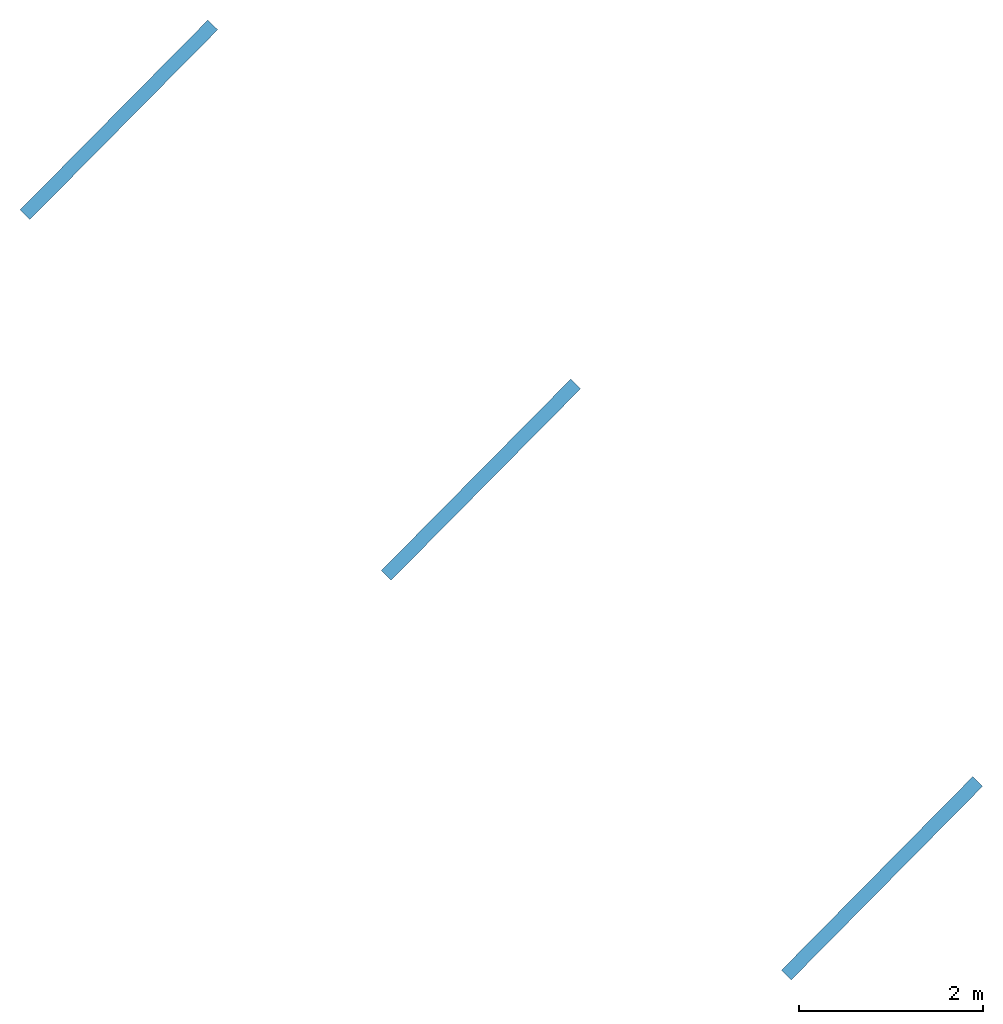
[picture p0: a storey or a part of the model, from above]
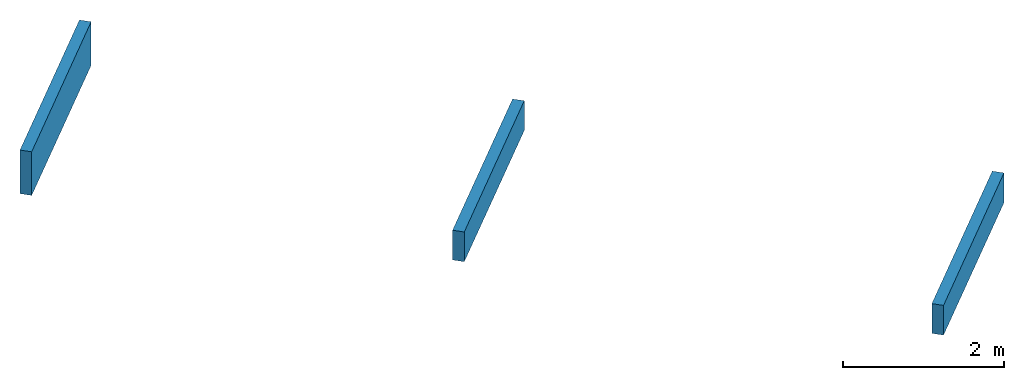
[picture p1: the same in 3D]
Properties of the parts of a building model (IFC2X3), part 1 of 2

# File
Description: ViewDefinition [CoordinationView]
File name: ZV001-350-201.1 (EDITED).ifc (Edited by Naviate Simple BIM 2022 version 6)
Time: 2026-03-20T15:17:01+01:00
Written by: ODA SDAI 24.12
Made in: Autodesk Revit 25.4.30.30 (ENU) - IFC 25.4.0.27

# IfcProject, 10001574
LongName: ENZV Kommersielt areal innland (KAI); Phase: Hovedprosjekt: 01.12.2018

# IfcSite, ENZV
RefLatitude: 59, 54, 57, 601318; RefLongitude: 10, 44, 59, 999999; RefElevation: 0 mm
Text - 02_IfcSite: STAVANGER LUFTHAVN; 01_Modellfil: zv001-a-200-1-0003.rvt; Prosjektleder: Livar Husveg; Tiltaket gjelder: Kommersielt areal innland, KAI
Identity Data - Building Name: ZV001; Inventarnr.: ZV001; CQIncludeDoorSwing: no; CQIncludeRoomNumber: no; CQIncludeRoomNumberWindows: no; CQIncludeWindowSwing: no; Workset: Project Info; Organization Description: BIM 360://Avinor - Stavanger lufthavn/ENZV_ARK_bygg A.rvt; Prosjekt: Stavanger lufthavn, Sola
Other - Project Number: 10001574; CQDoorSwingCodes: Left=V;Right=H;notMirrored =L;mirrored =R; Project Issue Date: Tilbudsprosjekt: 22.07.2018; CQWindowSwingCodes: Left=Rettv.;Right=Speilv.; Category: Project Information; Project Address: Enter address here; CQPhaseFilter: Existing:True;New Construction:True;Fase 2.0:True;Fase 3.0:True;Fase 3.9:True;Fase 4.0:True;Fase 5.1:True;Fase 5.2:True;Fase 5.3:True;Fase 5.4:True;Fase 5.9:True;Fase 5.10:True;Fase plot tegninger:True;Fase 6.0:True;; CQIncludeTemporaryDoors: no; Project Name: ENZV Kommersielt areal innland (KAI); Project Status: Hovedprosjekt: 01.12.2018; Tiltakshavers navn: Livar Husveg

# IfcBuilding, ZV001
LongName: ZV001
Other - Project Number: 10001574; CQDoorSwingCodes: Left=V;Right=H;notMirrored =L;mirrored =R; Project Issue Date: Tilbudsprosjekt: 22.07.2018; CQWindowSwingCodes: Left=Rettv.;Right=Speilv.; Category: Project Information; Project Address: Enter address here; CQPhaseFilter: Existing:True;New Construction:True;Fase 2.0:True;Fase 3.0:True;Fase 3.9:True;Fase 4.0:True;Fase 5.1:True;Fase 5.2:True;Fase 5.3:True;Fase 5.4:True;Fase 5.9:True;Fase 5.10:True;Fase plot tegninger:True;Fase 6.0:True;; CQIncludeTemporaryDoors: no; Project Name: ENZV Kommersielt areal innland (KAI); Project Status: Hovedprosjekt: 01.12.2018; Tiltakshavers navn: Livar Husveg
Pset_BuildingCommon - NumberOfStoreys: 8
Text - 02_IfcSite: STAVANGER LUFTHAVN; 01_Modellfil: zv001-a-200-1-0003.rvt; Prosjektleder: Livar Husveg; Tiltaket gjelder: Kommersielt areal innland, KAI
Identity Data - Building Name: ZV001; Inventarnr.: ZV001; CQIncludeDoorSwing: no; CQIncludeRoomNumber: no; CQIncludeRoomNumberWindows: no; CQIncludeWindowSwing: no; Workset: Project Info; Organization Description: BIM 360://Avinor - Stavanger lufthavn/ENZV_ARK_bygg A.rvt; Prosjekt: Stavanger lufthavn, Sola

# IfcBuildingStorey: Level:8mm Nivåhode Lokale Koter (2)
In: ZV001
Identity Data - Structural: no; Building Story: yes; Workset: Shared Levels and Grids
Other - Type Id: 305; Category: Levels; Family and Type: Level: 8mm Nivåhode Lokale Koter; Family: Level; Type: 8mm Nivåhode Lokale Koter
Graphics(Type) - Line Pattern: Centre; Color: 0; Symbol at End 1 Default: no; Symbol at End 2 Default: yes; Line Weight: 1; Symbol: View - Nivåhode1 : Nivåhode Trekant 2
Identity Data(Type) - Workset: Level Types; Type Name: 8mm Nivåhode Lokale Koter
Phasing - Fagkode: ARK
Constraints(Type) - Elevation Base: Project Base Point
Other(Type) - Category: Levels; Family Name: Level
Name | LongName = Identity Data, Name = Etasjekoder | Elevation (mm) = Constraints, Elevation (mm) | Computation Height (mm)
H01 | H01 | 5100 | 1200 | Pset_AirSideSystemInformation - Name: H01; sets with these values: 2
H02 | H02 | 9300 | 0 | Pset_ProductRequirements - Name: H02; sets with these values: 2

# IfcCovering: Compound Ceiling:ENZV_Eksisterende himling_600x600mm (3)
In: H02
Type - PredefinedType: CEILING
Type - Other - Category: Ceilings; Family Name: Compound Ceiling
Type - Construction - Thickness: 80 mm
Type - Graphics - Coarse Scale Fill Color: 0
Type - Identity Data - Type Mark: Eksisterende himl.; Type Name: ENZV_Eksisterende himling_600x600mm; Workset: Ceiling Types
Type - Analytical Properties - Absorptance: 0.1; Roughness: 1
Type - Pset_CoveringCommon - TotalThickness: 80 mm
ePset_SimplebimBasicQuantities - Height (Simplebim): 80 mm
Identity Data - Workset: Workset1
Pset_CoveringCommon - Reference: ENZV_Eksisterende himling_600x600mm; Finish: Systemhimling 600x600mm;
Pset_QuantityTakeOff - Reference: ENZV_Eksisterende himling_600x600mm
Constraints - Level: H02
ePset_Simplebim - Assembly Level: Leaf
Other - Family: Compound Ceiling; Type: ENZV_Eksisterende himling_600x600mm; Family and Type: Compound Ceiling: ENZV_Eksisterende himling_600x600mm; Type Id: 1873178
Phasing - Phase Created: Fase 1 - Som bygget
Name (Compound Ceiling:ENZV_Eksisterende himling_600x600mm:...) | Area, largest surface, net (Simplebim) (m2) | Length (Simplebim) (mm) | Volume, net (Simplebim) (m3) | Width (Simplebim) (mm) | Splitting | Room Bounding | 06_Omrade | 01_Lufthavnkode
2608000 | 74.0277 | 13426.7 | 5.92222 | 10848.3 | ORIGINAL | no | ZV001 | ENZV | Material: Standard 64 mm, Systemhimling 600x600mm 16 mm; Constraints - Height Offset From Level: 2950 mm; Dimensions - Area: 74.0277 m2; Volume: 5.92222 m3; Perimeter: 50553.6 mm
1624455 | 0.873786 | 9510 | 0.0251436 | 5397 | RESULT | yes | ZV001 | ENZV | AVINOR - 08_Status: S4; 03_Ansvar: 183205; 02_Prosjekt: 10001574; 07_Fase: F50
2625630 | 18.0009 | 8556 | 1.44007 | 3975 | RESULT | no

# IfcCovering: Compound Ceiling:ENZV_H02_Mineralullhimling 600x600mm, Compound Ceiling:ENZV_H02_Mineralullhimling 600x600mm:2671689
In: H02
Type - PredefinedType: CEILING
Type - Other - Category: Ceilings; Family Name: Compound Ceiling
Type - Construction - Thickness: 80 mm
Type - Graphics - Coarse Scale Fill Color: 0
Type - Identity Data - Type Mark: H02; Type Name: ENZV_H02_Mineralullhimling 600x600mm; Workset: Ceiling Types
Type - Analytical Properties - Absorptance: 0.1; Roughness: 1
Type - Pset_CoveringCommon - TotalThickness: 80 mm
Pset_CoveringCommon - Finish: Systemhimling 600x600mm;; Reference: ENZV_H02_Mineralullhimling 600x600mm
Identity Data - Workset: Workset1
Pset_QuantityTakeOff - Reference: ENZV_H02_Mineralullhimling 600x600mm
Constraints - Room Bounding: no; Level: H02
ePset_Simplebim - Assembly Level: Leaf
ePset_SimplebimBasicQuantities - Volume, net (Simplebim): 0.0203872 m3; Height (Simplebim): 80 mm; Width (Simplebim): 538 mm; Length (Simplebim): 947 mm; Area, largest surface, net (Simplebim): 0.25484 m2
AVINOR - 05_ID-nummer: +ZV001=257.0001-EH0020T; 08_Status: S4; 03_Ansvar: 183205; 07_Fase: F90; 02_Prosjekt: 10001574; 06_Omrade: ZV001; 01_Lufthavnkode: ENZV; 04_Kontrakt: 187993
ePset_LocationTool - Splitting: RESULT
Other - Type Id: 389170; Family and Type: Compound Ceiling: ENZV_H02_Mineralullhimling 600x600mm; Family: Compound Ceiling; Type: ENZV_H02_Mineralullhimling 600x600mm
Phasing - Phase Created: Fase 1 - Som bygget

# IfcCovering: Compound Ceiling:ENZV_H03_Hygienehimling 600x600mm, Compound Ceiling:ENZV_H03_Hygienehimling 600x600mm:1941711
In: H02
Type - PredefinedType: CEILING
Type - Other - Category: Ceilings; Family Name: Compound Ceiling
Type - Construction - Thickness: 52 mm
Type - Graphics - Coarse Scale Fill Color: 0
Type - Identity Data - Type Mark: H-03; Type Name: ENZV_H03_Hygienehimling 600x600mm; Workset: Ceiling Types
Type - Analytical Properties - Absorptance: 0.1; Roughness: 1
Type - Pset_CoveringCommon - TotalThickness: 52 mm
Identity Data - Workset: Workset1
ePset_SimplebimBasicQuantities - Area, largest surface, net (Simplebim): 0.61363 m2; Volume, net (Simplebim): 0.0319088 m3; Height (Simplebim): 52 mm; Width (Simplebim): 1461 mm; Length (Simplebim): 2319 mm
Constraints - Room Bounding: no; Level: H02
Pset_QuantityTakeOff - Reference: ENZV_H03_Hygienehimling 600x600mm
ePset_Simplebim - Assembly Level: Leaf
ePset_LocationTool - Splitting: RESULT
Pset_CoveringCommon - Finish: Systemhimling 600x600mm;; Reference: ENZV_H03_Hygienehimling 600x600mm
Other - Family: Compound Ceiling; Family and Type: Compound Ceiling: ENZV_H03_Hygienehimling 600x600mm; Type Id: 389169; Type: ENZV_H03_Hygienehimling 600x600mm
AVINOR - 08_Status: S4; 03_Ansvar: 183205; 07_Fase: F90; 02_Prosjekt: 10001574; 05_ID-nummer: +ZV001=257.0001-EH0018T; 06_Omrade: ZV001; 01_Lufthavnkode: ENZV; 04_Kontrakt: 187993
Phasing - Phase Created: Fase 1 - Som bygget

# IfcCovering: Compound Ceiling:ENZV_H04_Fast gipshimling, Compound Ceiling:ENZV_H04_Fast gipshimling:2637508
In: H02
Type - PredefinedType: CEILING
Type - Other - Category: Ceilings; Family Name: Compound Ceiling
Type - Construction - Thickness: 13 mm
Type - Graphics - Coarse Scale Fill Color: 16777215
Type - Identity Data - Type Mark: H04; Type Name: ENZV_H04_Fast gipshimling; Workset: Ceiling Types
Type - Analytical Properties - Absorptance: 0.1; Roughness: 1
Type - Pset_CoveringCommon - TotalThickness: 13 mm
Material: Gips 13 mm
Pset_QuantityTakeOff - Reference: ENZV_H04_Fast gipshimling; sets with these values: 2
ePset_LocationTool - Splitting: ORIGINAL
Identity Data - Workset: Workset1
ePset_SimplebimBasicQuantities - Height (Simplebim): 13 mm; Area, largest surface, net (Simplebim): 3.09942 m2; Length (Simplebim): 9587.21 mm; Width (Simplebim): 5694.76 mm; Volume, net (Simplebim): 0.0402925 m3
Dimensions - Perimeter: 22502.5 mm; Area: 3.09942 m2; Volume: 0.0402925 m3
Other - Type Id: 388737; Family and Type: Compound Ceiling: ENZV_H04_Fast gipshimling; Family: Compound Ceiling; Type: ENZV_H04_Fast gipshimling
ePset_Simplebim - Assembly Level: Leaf
Constraints - Room Bounding: no; Level: H02; Height Offset From Level: 2650 mm
AVINOR - 08_Status: S4; 03_Ansvar: 183205; 07_Fase: F90; 02_Prosjekt: 10001574; 06_Omrade: ZV001; 01_Lufthavnkode: ENZV; 05_ID-nummer: +ZV001=256.0001-EH0007T; 04_Kontrakt: 187993
Phasing - Phase Created: Fase 1 - Som bygget

# IfcCurtainWall: Curtain Wall:IGF-06, Curtain Wall:IGF-06:2602559
In: H02
Type - Other - Category: Walls; Family Name: Curtain Wall
Type - Construction - Function: Exterior; Automatically Embed: yes; Join Condition: Not Defined
Type - Identity Data - Workset: Curtain Wall Types; Type Mark: IGF-06; Type Name: IGF-06
Type - Horizontal Grid - Adjust for Mullion Size: no
Type - Vertical Grid - Adjust for Mullion Size: no
Phasing - Phase Created: Fase 1 - Som bygget
Other - Type Id: 2653210; Family and Type: Curtain Wall: IGF-06; Type: IGF-06; Family: Curtain Wall
Pset_CurtainWallCommon - Reference: IGF-06; IsExternal: yes
Identity Data - Workset: Workset1
Pset_QuantityTakeOff - Reference: IGF-06
Structural - Structural Usage: Non-bearing; Structural: no
AVINOR - 08_Status: S4; 03_Ansvar: 183205; 07_Fase: F90; 02_Prosjekt: 10001574; 06_Omrade: ZV001; 01_Lufthavnkode: ENZV; 05_ID-nummer: +ZV001=243.0001-AV0004T; 04_Kontrakt: 187993
ePset_SimplebimBasicQuantities - Length: 2982.67 mm; Volume, net (Simplebim): 0.0861992 m3; Width: 40 mm; Height: 2650 mm
Cross-Section Definition - Cross-Section: Vertical
ePset_Simplebim - Assembly Level: Topmost
Horizontal Grid - Angle: 0 deg; Offset: 0 mm; Number: 4; Justification: Beginning
Vertical Grid - Number: 4; Angle: 0 deg; Offset: 0 mm; Justification: Beginning
Dimensions - Length: 3068.35 mm; Area: 7.90408 m2
Constraints - Top Offset: -1250 mm; Top Constraint: Up to level: H03; Base is Attached: no; Related to Mass: no; Room Bounding: yes; Top is Attached: no; Base Offset: 0 mm; Base Constraint: H02; Unconnected Height: 2650 mm

# IfcCurtainWall: Curtain Wall:fasade (5)
In: H02
Type - Other(Type) - Category: Walls; Family Name: Curtain Wall
Type - Construction(Type) - Function: Exterior; Automatically Embed: yes; Join Condition: Not Defined
Type - Identity Data(Type) - Type Name: fasade; Workset: Curtain Wall Types
Type - Horizontal Grid(Type) - Adjust for Mullion Size: no
Type - Vertical Grid(Type) - Adjust for Mullion Size: no
Phasing - Phase Created: Fase 1 - Som bygget
Identity Data - Workset: Workset1
Pset_QuantityTakeOff - Reference: fasade
Structural - Structural Usage: Non-bearing; Structural: no
Constraints - Unconnected Height: 2780 mm; Top Constraint: Up to level: H03; Base is Attached: no; Related to Mass: no; Room Bounding: yes; Top is Attached: no; Base Constraint: H02; Top Offset: -720 mm; Base Offset: 400 mm
Cross-Section Definition - Cross-Section: Vertical
Other - Type: fasade; Type Id: 556345; Family and Type: Curtain Wall: fasade; Category: Walls; Family: Curtain Wall
ePset_Simplebim - Assembly Level: Topmost
Horizontal Grid - Angle: 0 deg; Offset: 0 mm; Number: 4; Justification: Beginning
Vertical Grid - Number: 4; Angle: 0 deg; Offset: 0 mm; Justification: Beginning
Pset_CurtainWallCommon - Reference: fasade; IsExternal: yes
ePset_SimplebimBasicQuantities - Height: 2780 mm
Name (Curtain Wall:fasade:...) | Area (m2) | Dimensions, Length (mm) | Width (mm) | ePset_SimplebimBasicQuantities, Length (mm) | Volume, net (Simplebim) (m3)
746721 | 20.85 | 7500 | 3849.99 | 6594.65 | 0.499135
749622 | 20.85 | 7500 | 3820.35 | 6545.24 | 0.463958
749650 | 21.545 | 7873 | 3973.52 | 6787.29 | 0.589405
750153 | 17.9419 | 6507.48 | 200 | 6453.94 | 0.406707
754297 | 1.45207 | 575.87 | 431.964 | 552.935 | 0.0990327

# IfcDoor: A244-Enfløyet1:DT03_Tredør 10x21M, A244-Enfløyet1:DT03_Tredør 10x21M:2601241
In: H02
Type - OperationType: SINGLE_SWING_LEFT; ConstructionType: USERDEFINED; ParameterTakesPrecedence: no; Sizeable: no; Material: Rustfritt Stål, Høytrykkslaminat, Uten terskel, Tre
Type - IfcDoorPanelProperties - PanelOperation: SWINGING
Type - Other - Category: Doors; Family Name: A244-Enfløyet1; Karmfalsbredde: 22 mm; M_Height: 21; M_Width: 10
Type - Constraints - CQOriginalSwingDirection: Left
Type - Construction - Function: Interior; Construction Type: TD Tredør; Dørblad i plan: no; Dørklinke: Dørklinke - Enkel : Rustfritt; Terskel: yes; Terskeltype: Terskeltype; Wall Closure: By host
Type - Dimensions - Karmbredde: 42 mm; Karmdybde: 100 mm; Karmprofil: 20 mm; Rough Height: 2090 mm; Rough Width: 990 mm; Thickness: 40 mm
Type - Identity Data - CQSwingCount: 12H/13V; CQTypeCount: 25; Description: Kompaktdør med laminatoverflate; DoorBasalOpening: V; Fire Rating: -; Type Mark: DT03; Type Name: DT03_Tredør 10x21M; URL: www.cad-q.no; Workset: Family : Doors : A244-Enfløyet1; AcousticRating: -
Type - Materials and Finishes - Dørbladmateriale: Høytrykkslaminat; Karmmateriale: Tre; Terskelmateriale: Uten terskel
Type - Text - Kantlist: Eik; Karm S: Tre
Type - Analytical Properties - Define Thermal Properties by: Schematic Type; Analytic Construction: <None>
Type - Pset_ConcreteElementGeneral - FireRating: -; ConstructionType: TD Tredør
Type - Pset_DoorCommon - FireRating: -; AcousticRating: -
OverallHeight: 2110 mm; OverallWidth: 1010 mm
Pset_QuantityTakeOff - Reference: DT03_Tredør 10x21M
Text - Fargekode: NCS S 0502-Y; Terskel: Uten terskel; Låskasse: X; Vrider: X
Identity Data - Mark: A2722.1; CQSwingDirection: H; 08_Brannkrav: -; Workset: Workset1; Comments: Vrider med kodetast.
Pset_DoorCommon - IsExternal: no; Reference: DT03_Tredør 10x21M
Other - Sparkeplate: Begge sider, h 300mm; Family: A244-Enfløyet1; Host Id: 2610438; Dørstopper: X; Innsetoffset: 1020 mm; Head Height: 2110 mm; Type: DT03_Tredør 10x21M; Type Id: 1660446; Family and Type: A244-Enfløyet1: DT03_Tredør 10x21M
Dimensions - Area: 2.82915 m2; Volume: 0.090268 m3; Spalte Side: 10 mm; Innsetting Dør: 20 mm; Spalte Topp: 20 mm; Veggtykkelse: 133 mm; Width: 1010 mm; Height: 2110 mm
ePset_SimplebimBasicQuantities - Length, frame (Simplebim): 5170 mm; Height, opening (Simplebim): 2110 mm; Height (Simplebim): 2090 mm; Area (Simplebim): 2.0691 m2; Width (Simplebim): 990 mm; Width, opening (Simplebim): 1010 mm; Area, opening (Simplebim): 2.1311 m2
AVINOR - 08_Status: S4; 03_Ansvar: 183205; 07_Fase: F90; 02_Prosjekt: 10001574; 06_Omrade: ZV001; 01_Lufthavnkode: ENZV; 05_ID-nummer: +ZV001=244.0206-DI0099; 04_Kontrakt: 187993
Constraints - Sill Height: 0 mm; Level: H02
Phasing - Phase Created: Fase 1 - Som bygget
ePset_Simplebim - Assembly Level: Leaf
ePset_LocationTool - Splitting: ORIGINAL

# IfcDoor: Enfløyet:Dør 10x21M, Enfløyet:Dør 10x21M:2612558
In: H02
Type - OperationType: SINGLE_SWING_RIGHT; ParameterTakesPrecedence: no; Sizeable: no; Material: Rustfritt Stål, Hvit
Type - IfcDoorPanelProperties - PanelOperation: SWINGING
Type - Other - Category: Doors; Family Name: Enfløyet; Karmfalsbredde: 30 mm; M_Height: 21; M_Width: 10
Type - Constraints - CQOriginalSwingDirection: Left
Type - Construction - Function: Interior; Dørblad i plan: no; Dørklinke: Dørklinke - Enkel : Rustfritt; Terskel: no; Terskeltype: Terskeltype; Wall Closure: By host
Type - Dimensions - Karmbredde: 42 mm; Karmdybde: 100 mm; Karmprofil: 12 mm; Rough Height: 2090 mm; Rough Width: 990 mm; Thickness: 40 mm
Type - Identity Data - Fire Rating: -; Type Mark: D - 10x21M; Type Name: Dør 10x21M; URL: www.cad-q.no; Workset: Family : Doors : Enfløyet
Type - Materials and Finishes - Dørbladmateriale: Hvit; Karmmateriale: Hvit; Terskelmateriale: Tre
Type - Analytical Properties - Define Thermal Properties by: Schematic Type; Analytic Construction: <None>
Type - Pset_ConcreteElementGeneral - FireRating: -
Type - Pset_DoorCommon - FireRating: -
OverallHeight: 2110 mm; OverallWidth: 1010 mm
Dimensions - Innsetting Dør: 0 mm; Volume: 0.09176 m3; Spalte Side: 10 mm; Spalte Topp: 20 mm; Veggtykkelse: 75 mm; Width: 1010 mm; Height: 2110 mm; Area: 2.82579 m2
Identity Data - 08_Brannkrav: -; Mark: A2702.13; Workset: Workset1
Pset_QuantityTakeOff - Reference: Dør 10x21M
ePset_SimplebimBasicQuantities - Length, frame (Simplebim): 5170 mm; Height, opening (Simplebim): 2110 mm; Height (Simplebim): 2090 mm; Area (Simplebim): 2.0691 m2; Width (Simplebim): 990 mm; Width, opening (Simplebim): 1010 mm; Area, opening (Simplebim): 2.1311 m2
Pset_DoorCommon - IsExternal: no; Reference: Dør 10x21M
Constraints - Sill Height: 0 mm; Level: H02
Phasing - Phase Created: Fase 1 - Som bygget
ePset_LocationTool - Splitting: ORIGINAL
ePset_Simplebim - Assembly Level: Leaf
Other - Family: Enfløyet; Type Id: 414931; Family and Type: Enfløyet: Dør 10x21M; Type: Dør 10x21M; Innsetoffset: 1000 mm; Head Height: 2110 mm; Host Id: 2607600

# IfcMember: Rectangular Mullion:50x200mm (24)
In: H02
Type - PredefinedType: MULLION; Material: Aluminium
Type - Other - Category: Curtain Wall Mullions; Family Name: Rectangular Mullion
Type - Constraints - Angle: 0 deg; Offset: 0 mm
Type - Construction - Corner Mullion: no; Position: Perpendicular to Face; Profile: System Mullion Profile: Rectangular; Thickness: 200 mm
Type - Dimensions - Width on side 1: 25 mm; Width on side 2: 25 mm
Type - Identity Data - Type Name: 50x200mm; Workset: Family : Curtain Wall Mullions : Rectangular Mullion
Type - Materials and Finishes - Material: Aluminium
Identity Data - Workset: Workset1
Pset_MemberCommon - IsExternal: yes; Reference: 50x200mm
Pset_QuantityTakeOff - Reference: 50x200mm
Other - Family: Rectangular Mullion; Family and Type: Rectangular Mullion: 50x200mm; Type: 50x200mm; Type Id: 746326
Phasing - Phase Created: Fase 1 - Som bygget
ePset_LocationTool - Splitting: ORIGINAL
ePset_Simplebim - Assembly Level: Leaf
Constraints - Level: H02
Name (Rectangular Mullion:50x200mm:...) | Span (mm) = Length (mm) | Host Id | Height (Simplebim) (mm) | Area, sides, net (Simplebim) (m2) | Width (Simplebim) (mm) | Length (Simplebim) (mm) | Volume, net (Simplebim) (m3) = Volume (m3) | Weight, as steel (Simplebim) (kg) | Area (m2)
746731 | 2780 | 746721 | 2780 | 1.41 | 50 | 200 | 0.0278 | 218.23 | 0.705
746732 | 2780 | 746721 | 2780 | 1.41 | 50 | 200 | 0.0278 | 218.23 | 0.705
748356 | 2780 | 746721 | 2780 | 1.41 | 50 | 200 | 0.0278 | 218.23 | 0.705
748359 | 2780 | 746721 | 2780 | 1.41 | 50 | 200 | 0.0278 | 218.23 | 0.705
748362 | 2393 | 746721 | 50 | 1.2165 | 200 | 2393 | 0.02393 | 187.851 | 0.60825
748363 | 2394 | 746721 | 50 | 1.217 | 200 | 2394 | 0.02394 | 187.929 | 0.6085
748364 | 2373 | 746721 | 50 | 1.2065 | 200 | 2373 | 0.02373 | 186.28 | 0.60325
748374 | 2373 | 746721 | 50 | 1.2065 | 200 | 2373 | 0.02373 | 186.28 | 0.60325
748376 | 2393 | 746721 | 50 | 1.2165 | 200 | 2393 | 0.02393 | 187.851 | 0.60825
748377 | 2394 | 746721 | 50 | 1.217 | 200 | 2394 | 0.02394 | 187.929 | 0.6085
749628 | 2780 | 749622 | 2780 | 1.41 | 50 | 200 | 0.0278 | 218.23 | 0.705
749629 | 2780 | 749622 | 2780 | 1.41 | 50 | 200 | 0.0278 | 218.23 | 0.705
749634 | 2780 | 749622 | 2780 | 1.41 | 50 | 200 | 0.0278 | 218.23 | 0.705
749635 | 2780 | 749622 | 2780 | 1.41 | 50 | 200 | 0.0278 | 218.23 | 0.705
749636 | 2393 | 749622 | 50 | 1.2165 | 200 | 2393 | 0.02393 | 187.851 | 0.60825
749637 | 2394 | 749622 | 50 | 1.217 | 200 | 2394 | 0.02394 | 187.929 | 0.6085
749638 | 2393 | 749622 | 50 | 1.2165 | 200 | 2393 | 0.02393 | 187.851 | 0.60825
749639 | 2393 | 749622 | 50 | 1.2165 | 200 | 2393 | 0.02393 | 187.851 | 0.60825
749640 | 2393 | 749622 | 50 | 1.2165 | 200 | 2393 | 0.02393 | 187.851 | 0.60825
749641 | 2394 | 749622 | 50 | 1.217 | 200 | 2394 | 0.02394 | 187.929 | 0.6085
749663 | 2780 | 749650 | 2780 | 1.41 | 50 | 200 | 0.0278 | 218.23 | 0.705
752525 | 2780 | 750153 | 2780 | 1.41 | 50 | 200 | 0.0278 | 218.23 | 0.705
754689 | 2780 | 754297 | 2780 | 1.41 | 50 | 200 | 0.0278 | 218.23 | 0.705
754692 | 2780 | 754297 | 2780 | 1.41 | 50 | 200 | 0.0278 | 218.23 | 0.705

# IfcMember: Rectangular Mullion:Drivhus 40x40mm (4)
In: H02
Type - PredefinedType: MULLION; Material: Aluminium
Type - Other - Category: Curtain Wall Mullions; Family Name: Rectangular Mullion
Type - Constraints - Angle: 0 deg; Offset: 0 mm
Type - Construction - Corner Mullion: no; Position: Perpendicular to Face; Profile: System Mullion Profile: Rectangular; Thickness: 40 mm
Type - Dimensions - Width on side 1: 20 mm; Width on side 2: 20 mm
Type - Identity Data - Type Name: Drivhus 40x40mm; Workset: Family : Curtain Wall Mullions : Rectangular Mullion
Type - Materials and Finishes - Material: Aluminium
Other - Family and Type: Rectangular Mullion: Drivhus 40x40mm; Type: Drivhus 40x40mm; Family: Rectangular Mullion; Type Id: 1629229; Host Id: 2602559
Identity Data - Workset: Workset1
Pset_QuantityTakeOff - Reference: Drivhus 40x40mm
Pset_MemberCommon - Reference: Drivhus 40x40mm; IsExternal: yes
AVINOR - 08_Status: S4; 03_Ansvar: 183205; 07_Fase: F90; 02_Prosjekt: 10001574; 06_Omrade: ZV001; 01_Lufthavnkode: ENZV; 05_ID-nummer: +ZV001=243.0001-AV0004T; 04_Kontrakt: 187993
ePset_LocationTool - Splitting: ORIGINAL
Phasing - Phase Created: Fase 1 - Som bygget
ePset_Simplebim - Assembly Level: Leaf
ePset_SimplebimBasicQuantities - Height (Simplebim): 40 mm; Width (Simplebim): 40 mm
Constraints - Level: H02
Name (Rectangular Mullion:Drivhus 40x40mm:...) | Volume (m3) = Volume, net (Simplebim) (m3) | Length (mm) = Span (mm) = Length (Simplebim) (mm) | Area (m2) | Weight, as steel (Simplebim) (kg) | Area, sides, net (Simplebim) (m2)
2636253 | 0.00232644 | 1454.03 | 0.117922 | 18.2626 | 0.235844
2636254 | 0.00244583 | 1528.64 | 0.123892 | 19.1998 | 0.247783
2636265 | 0.00244583 | 1528.64 | 0.123892 | 19.1998 | 0.247783
2636266 | 0.00232644 | 1454.03 | 0.117922 | 18.2626 | 0.235844

# IfcPlate: System Panel:Glassfelt 10mm (7)
In: H02
Type - PredefinedType: CURTAIN_PANEL; Material: Glass
Type - Other - Category: Curtain Panels; Family Name: System Panel
Type - Constraints - Offset: 0 mm
Type - Dimensions - Thickness: 10 mm
Type - Identity Data - Type Name: Glassfelt 10mm; Workset: Family : Curtain Panels : System Panel
Type - Materials and Finishes - Material: Glass
Type - Analytical Properties - Analytic Construction: <None>; Define Thermal Properties by: Schematic Type
Other - Type Id: 128792; Type: Glassfelt 10mm; Family: System Panel; Family and Type: System Panel: Glassfelt 10mm
Pset_PlateCommon - Reference: Glassfelt 10mm; IsExternal: yes
ePset_LocationTool - Splitting: ORIGINAL
Phasing - Phase Created: Fase 1 - Som bygget
Pset_QuantityTakeOff - Reference: Glassfelt 10mm
ePset_Simplebim - Assembly Level: Leaf
Constraints - Level: H02
Identity Data - Workset: Workset1
Name (System Panel:Glassfelt 10mm:...) | Host Id | Volume, net (Simplebim) (m3) | Area, largest surface, net (Simplebim) (m2) | Weight, as steel (Simplebim) (kg) | Volume (m3) | Width (mm) | Height (mm) | Area (m2)
748083 | 746721 | 0.0635964 | 6.35964 | 499.232 | 0.0635964 | 2373 | 2680 | 6.35964
746725 | 746721 | 0.0641592 | 6.41592 | 503.65 | 0.0641592 | 2394 | 2680 | 6.41592
746727 | 746721 | 0.0641592 | 6.41592 | 503.65 | 0.0641324 | 2393 | 2680 | 6.41324
749633 | 749622 | 0.0641592 | 6.41592 | 503.65 | 0.0641324 | 2393 | 2680 | 6.41324
749625 | 749622 | 0.0641592 | 6.41592 | 503.65 | 0.0641592 | 2394 | 2680 | 6.41592
749627 | 749622 | 0.0641592 | 6.41592 | 503.65 | 0.0641324 | 2393 | 2680 | 6.41324
754676 | 754297 | 0.0100727 | 1.00727 | 79.0711 | 0.0100727 | 362.329 | 2780 | 1.00727

# IfcPlate: System Panel:Glassfelt_limte skjøter (2)
In: H02
Type - PredefinedType: CURTAIN_PANEL; Material: Glass
Type - Other - Category: Curtain Panels; Family Name: System Panel
Type - Constraints - Offset: 0 mm
Type - Dimensions - Thickness: 10 mm
Type - Identity Data - Type Name: Glassfelt_limte skjøter; Workset: Family : Curtain Panels : System Panel
Type - Materials and Finishes - Material: Glass
Type - Analytical Properties - Analytic Construction: <None>; Define Thermal Properties by: Schematic Type
ePset_LocationTool - Splitting: ORIGINAL
Pset_QuantityTakeOff - Reference: Glassfelt_limte skjøter
AVINOR - 08_Status: S4; 03_Ansvar: 183205; 07_Fase: F90; 02_Prosjekt: 10001574; 06_Omrade: ZV001; 01_Lufthavnkode: ENZV; 05_ID-nummer: +ZV001=243.0001-AV0004T; 04_Kontrakt: 187993
Pset_PlateCommon - IsExternal: yes; Reference: Glassfelt_limte skjøter
Other - Type Id: 2660169; Family and Type: System Panel: Glassfelt_limte skjøter; Host Id: 2602559; Type: Glassfelt_limte skjøter; Family: System Panel
Phasing - Phase Created: Fase 1 - Som bygget
ePset_Simplebim - Assembly Level: Leaf
Constraints - Level: H02
Dimensions - Height: 2570 mm
Identity Data - Workset: Workset1
Name (System Panel:Glassfelt_limte skjøter:...) | Weight, as steel (Simplebim) (kg) | Area, largest surface, net (Simplebim) (m2) = Area (m2) | Volume, net (Simplebim) (m3) = Volume (m3) | Width (mm)
2602560 | 308.396 | 3.92862 | 0.0392862 | 1528.64
2636223 | 293.343 | 3.73685 | 0.0373685 | 1454.03

# IfcPlate: System Panel:Tettfelt 200 (2)
In: H02
Type - PredefinedType: CURTAIN_PANEL; Material: Default
Type - Other - Category: Curtain Panels; Family Name: System Panel
Type - Constraints - Offset: 0 mm
Type - Dimensions - Thickness: 200 mm
Type - Identity Data - Type Name: Tettfelt 200; Workset: Family : Curtain Panels : System Panel
Type - Materials and Finishes - Material: Default
Type - Analytical Properties - Analytic Construction: <None>; Define Thermal Properties by: Schematic Type
Pset_PlateCommon - Reference: Tettfelt 200; IsExternal: yes
Pset_QuantityTakeOff - Reference: Tettfelt 200
Other - Type: Tettfelt 200; Family and Type: System Panel: Tettfelt 200; Type Id: 753742; Family: System Panel
ePset_SimplebimBasicQuantities - Area, largest surface, net (Simplebim): 0.556 m2
ePset_LocationTool - Splitting: ORIGINAL
Phasing - Phase Created: Fase 1 - Som bygget
Dimensions - Height: 2780 mm
ePset_Simplebim - Assembly Level: Leaf
Constraints - Level: H02
Identity Data - Workset: Workset1
Name (System Panel:Tettfelt 200:...) | Host Id | Volume, net (Simplebim) (m3) = Volume (m3) | Weight, as steel (Simplebim) (kg) | Width (mm) | Area (m2)
746722 | 746721 | 0.04448 | 349.168 | 80 | 0.2224
754298 | 754297 | 0.03336 | 261.876 | 60 | 0.1668

# IfcPlate: System Panel:Tettfelt 50mm (4)
In: H02
Type - PredefinedType: CURTAIN_PANEL; Material: Default
Type - Other - Category: Curtain Panels; Family Name: System Panel
Type - Constraints - Offset: 25 mm
Type - Dimensions - Thickness: 50 mm
Type - Identity Data - Type Name: Tettfelt 50mm; Workset: Family : Curtain Panels : System Panel
Type - Materials and Finishes - Material: Default
Type - Analytical Properties - Analytic Construction: <None>; Define Thermal Properties by: Schematic Type
ePset_LocationTool - Splitting: ORIGINAL
Pset_PlateCommon - Reference: Tettfelt 50mm; IsExternal: yes
ePset_SimplebimBasicQuantities - Volume, net (Simplebim): 0.00834008 m3; Area, largest surface, net (Simplebim): 0.166802 m2; Weight, as steel (Simplebim): 65.4696 kg
Phasing - Phase Created: Fase 1 - Som bygget
Dimensions - Height: 2780 mm
ePset_Simplebim - Assembly Level: Leaf
Constraints - Level: H02
Pset_QuantityTakeOff - Reference: Tettfelt 50mm
Identity Data - Workset: Workset1
Other - Type Id: 190679; Type: Tettfelt 50mm; Family: System Panel; Family and Type: System Panel: Tettfelt 50mm
Name (System Panel:Tettfelt 50mm:...) | Width (mm) | Volume (m3) | Area (m2) | Host Id
748040 | 60.0006 | 0.00834008 | 0.166802 | 746721
749623 | 59.9994 | 0.00833992 | 0.166798 | 749622
749631 | 60.0011 | 0.00834016 | 0.166803 | 749622
749651 | 59.9989 | 0.00833984 | 0.166797 | 749650

# IfcSlab: Floor:ENZV_G03_Banebelegg vinyl, Floor:ENZV_G03_Banebelegg vinyl:2615882
In: H02
Type - PredefinedType: FLOOR; Material: Gulv - Vinyl 2.5 mm, Avretting 12.5 mm
Type - Other - Category: Floors; Family Name: Floor
Type - Construction - Default Thickness: 15 mm; Function: Interior
Type - Graphics - Coarse Scale Fill Color: 6974058; Coarse Scale Fill Pattern: Vinyl
Type - Identity Data - Type Name: ENZV_G03_Banebelegg vinyl; Workset: Floor Types; Type Mark: G03
Type - Materials and Finishes - Structural Material: Avretting
Type - Analytical Properties - Absorptance: 0.1; Roughness: 1
ePset_SimplebimBasicQuantities - Area, top, net (Simplebim): 14.6729 m2; Area, sides, net (Simplebim): 0.245505 m2; Perimeter (Simplebim): 16367 mm; Area, largest surface, net (Simplebim): 14.673 m2; Thickness (Simplebim): 15 mm; Volume, net (Simplebim): 0.220094 m3
Pset_QuantityTakeOff - Reference: ENZV_G03_Banebelegg vinyl; sets with these values: 2
Identity Data - Has Association: no; Workset: Workset1
Structural - Structural: no
Dimensions - Area: 14.6729 m2; Perimeter: 16369.3 mm; Thickness: 15 mm; Elevation at Bottom: 9285 mm; Elevation at Bottom Core: 9285 mm; Elevation at Top: 9300 mm; Elevation at Top Core: 9300 mm; Volume: 0.220094 m3
Other - Type Id: 2582780; Family and Type: Floor: ENZV_G03_Banebelegg vinyl; Type: ENZV_G03_Banebelegg vinyl; Family: Floor
Phasing - Phase Created: Fase 1 - Som bygget
Constraints - Related to Mass: no; Room Bounding: yes; Height Offset From Level: 0 mm; Level: H02
ePset_Simplebim - Assembly Level: Leaf
ePset_LocationTool - Splitting: ORIGINAL
Pset_SlabCommon - LoadBearing: no; IsExternal: no; PitchAngle: 0 deg; Reference: ENZV_G03_Banebelegg vinyl

# IfcSlab: Floor:ENZV_G04_Flis mørk grå 6x6M, Floor:ENZV_G04_Flis mørk grå 6x6M:1964547
In: H02
Type - PredefinedType: FLOOR; Material: Fliser 600x600mm mørk grå 15 mm
Type - Other - Category: Floors; Family Name: Floor
Type - Construction - Default Thickness: 15 mm; Function: Interior
Type - Graphics - Coarse Scale Fill Color: 0
Type - Identity Data - Type Name: ENZV_G04_Flis mørk grå 6x6M; Workset: Floor Types; Type Mark: G04
Type - Materials and Finishes - Structural Material: Fliser 600x600mm mørk grå
Type - Analytical Properties - Absorptance: 0.1; Roughness: 1
Constraints - Related to Mass: no; Room Bounding: yes; Level: H02
Other - Type: ENZV_G04_Flis mørk grå 6x6M; Family and Type: Floor: ENZV_G04_Flis mørk grå 6x6M; Type Id: 1166211; Family: Floor
Identity Data - Has Association: no; Workset: Workset1
Structural - Structural: no
Pset_ReinforcementBarPitchOfSlab - Reference: ENZV_G04_Flis mørk grå 6x6M; sets with these values: 2
Pset_SlabCommon - Reference: ENZV_G04_Flis mørk grå 6x6M; LoadBearing: no; IsExternal: no
Phasing - Phase Created: Fase 1 - Som bygget
ePset_SimplebimBasicQuantities - Area, largest surface, net (Simplebim): 0.613553 m2; Volume, net (Simplebim): 0.00920292 m3; Area, sides, net (Simplebim): 0.0831095 m2; Thickness (Simplebim): 15 mm; Area, top, net (Simplebim): 0.613562 m2; Perimeter (Simplebim): 5540.63 mm
ePset_Simplebim - Assembly Level: Leaf
ePset_LocationTool - Splitting: RESULT
AVINOR - 05_ID-nummer: +ZV001=255.0001-EB0020T; 08_Status: S4; 03_Ansvar: 183205; 07_Fase: F90; 02_Prosjekt: 10001574; 06_Omrade: ZV001; 01_Lufthavnkode: ENZV; 04_Kontrakt: 187993

# IfcSlab: Floor:Standard 325mm, Floor:Standard 325mm:758968
In: H02
Type - PredefinedType: FLOOR; Material: Hvit 325 mm
Type - Other - Category: Floors; Family Name: Floor
Type - Construction - Default Thickness: 325 mm; Function: Interior
Type - Graphics - Coarse Scale Fill Color: 0
Type - Identity Data - Type Name: Standard 325mm; Workset: Floor Types
Type - Materials and Finishes - Structural Material: Hvit
Type - Analytical Properties - Absorptance: 0.1; Roughness: 1
ePset_LocationTool - Splitting: RESULT
Constraints - Related to Mass: no; Room Bounding: yes; Level: H02
Other - Family and Type: Floor: Standard 325mm; Type: Standard 325mm; Type Id: 758970; Family: Floor
Identity Data - Has Association: no; Workset: Workset1
Structural - Structural: no
Pset_ReinforcementBarPitchOfSlab - Reference: Standard 325mm; sets with these values: 2
Pset_SlabCommon - Reference: Standard 325mm; LoadBearing: no; IsExternal: no
Phasing - Phase Created: Fase 1 - Som bygget
ePset_Simplebim - Assembly Level: Leaf
ePset_SimplebimBasicQuantities - Area, top, net (Simplebim): 127.089 m2; Area, largest surface, net (Simplebim): 127.09 m2; Perimeter (Simplebim): 47768.9 mm; Thickness (Simplebim): 325 mm; Volume, net (Simplebim): 41.3042 m3; Area, sides, net (Simplebim): 15.5249 m2

# IfcSlab: Floor:Standard 330mm betong (2)
In: H02
Type - PredefinedType: FLOOR; Material: Betong - Plasstøpt 330 mm
Type - Other - Category: Floors; Family Name: Floor
Type - Construction - Default Thickness: 330 mm; Function: Interior
Type - Graphics - Coarse Scale Fill Color: 0
Type - Identity Data - Type Name: Standard 330mm betong; Workset: Floor Types
Type - Materials and Finishes - Structural Material: Betong - Plasstøpt
Type - Analytical Properties - Absorptance: 0.1; Roughness: 1
Pset_SlabCommon - Reference: Standard 330mm betong; LoadBearing: no; IsExternal: no
Pset_QuantityTakeOff - Reference: Standard 330mm betong; sets with these values: 2
Constraints - Related to Mass: no; Room Bounding: yes; Level: H02
ePset_LocationTool - Splitting: RESULT
Identity Data - Has Association: no; Workset: Workset1
Structural - Structural: no
Phasing - Phase Created: Fase 1 - Som bygget
ePset_Simplebim - Assembly Level: Leaf
Other - Family and Type: Floor: Standard 330mm betong; Type: Standard 330mm betong; Type Id: 2906811; Family: Floor
ePset_SimplebimBasicQuantities - Area, top, net (Simplebim): 127.089 m2; Area, largest surface, net (Simplebim): 127.09 m2; Area, sides, net (Simplebim): 15.7637 m2; Perimeter (Simplebim): 47768.9 mm; Volume, net (Simplebim): 41.9396 m3; Thickness (Simplebim): 330 mm
Name (Floor:Standard 330mm betong:...)
3040182
3043625

# IfcWall: Basic Wall:ENZV_PV-UK01_S70_95mm_OSBG m wrap, Basic Wall:ENZV_PV-UK01_S70_95mm_OSBG m wrap:2336404
In: H02
Type - PredefinedType: STANDARD; Material: A246.Gips 12.5mm fiberarmert -QK5.31112 13 mm, OSB plate 12 mm, A242.Stender Lettmetall 95mm -PJ3.111002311 70 mm
Type - Other - Category: Walls; Family Name: Basic Wall
Type - Construction - Function: Interior; Width: 95 mm; Wrapping at Ends: Exterior; Wrapping at Inserts: Do not wrap; CQMaxWallHeight: 6000 mm
Type - Graphics - Coarse Scale Fill Color: 0
Type - Identity Data - Type Name: ENZV_PV-UK01_S70_95mm_OSBG m wrap; Workset: Wall Types; Type Mark: PV-UK01
Type - Analytical Properties - Absorptance: 0.1; Roughness: 1
Type - Materials and Finishes - Structural Material: A242.Stender Lettmetall 95mm -PJ3.111002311
Type - Text - Veggtype S: ENZV_PV-UK01_S70_95mm_OSBG
Pset_WallCommon - Reference: ENZV_PV-UK01_S70_95mm_OSBG m wrap; IsExternal: no; ExtendToStructure: no; LoadBearing: no
Cross-Section Definition - Cross-Section: Vertical
AVINOR - 05_ID-nummer: +ZV001=242.0001-AV0113; 08_Status: S4; 03_Ansvar: 183205; 07_Fase: F90; 02_Prosjekt: 10001574; 06_Omrade: ZV001; 01_Lufthavnkode: ENZV; 04_Kontrakt: 187993
Other - Family: Basic Wall; Type: ENZV_PV-UK01_S70_95mm_OSBG m wrap; Family and Type: Basic Wall: ENZV_PV-UK01_S70_95mm_OSBG m wrap; Type Id: 2282029
Pset_QuantityTakeOff - Reference: ENZV_PV-UK01_S70_95mm_OSBG m wrap; sets with these values: 2
Structural - Structural Usage: Non-bearing; Structural: no
ePset_LocationTool - Splitting: RESULT
Identity Data - Workset: Workset1
Phasing - Phase Created: Fase 1 - Som bygget
Constraints - Top Constraint: Up to level: H03; Base is Attached: no; Related to Mass: no; Room Bounding: yes; Top is Attached: no; Base Constraint: H02; Location Line: Core Face: Exterior
ePset_Simplebim - Assembly Level: Leaf
ePset_SimplebimBasicQuantities - Area, side, gross, average (Simplebim): 1.11456 m2; Area, side, net, average (Simplebim): 1.11456 m2; Volume, net (Simplebim): 0.105883 m3; Area, side, gross, AABB (Simplebim): 1.11319 m2; Area, side, gross, larger (Simplebim): 1.11456 m2; Area, side, net, larger (Simplebim): 1.11456 m2; Area, largest surface, net (Simplebim): 1.11456 m2; Thickness (Simplebim): 96 mm; Length (Simplebim): 397 mm; Height (Simplebim): 2804 mm; Area, side, gross, smaller (Simplebim): 1.11456 m2; Area, side, net, smaller (Simplebim): 1.11456 m2

# IfcWall: Basic Wall:ENZV_S-UK01_S70_120mm_OSBG, Basic Wall:ENZV_S-UK01_S70_120mm_OSBG:1233238
In: H02
Type - PredefinedType: STANDARD; Material: A246.Gips 12.5mm fiberarmert -QK5.31112 13 mm, OSB plate 12 mm, A242.Stender Lettmetall 95mm -PJ3.111002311 70 mm, OSB plate 12 mm, A246.Gips 12.5mm fiberarmert -QK5.31112 13 mm
Type - Other - Category: Walls; Family Name: Basic Wall
Type - Construction - Function: Interior; Width: 120 mm; Wrapping at Inserts: Do not wrap; CQMaxWallHeight: 6000 mm
Type - Graphics - Coarse Scale Fill Color: 0
Type - Identity Data - Type Name: ENZV_S-UK01_S70_120mm_OSBG; Workset: Wall Types; Type Mark: S-UK01
Type - Analytical Properties - Absorptance: 0.1; Roughness: 1
Type - Materials and Finishes - Structural Material: A242.Stender Lettmetall 95mm -PJ3.111002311
Type - Text - Veggtype S: ENZV_S-UK01_S95_145mm_OSBG
Pset_ReinforcementBarPitchOfWall - Reference: ENZV_S-UK01_S70_120mm_OSBG; sets with these values: 2
Other - Type: ENZV_S-UK01_S70_120mm_OSBG; Family: Basic Wall; Family and Type: Basic Wall: ENZV_S-UK01_S70_120mm_OSBG; Type Id: 1646284
Cross-Section Definition - Cross-Section: Vertical
Structural - Structural Usage: Non-bearing; Structural: no
AVINOR - 08_Status: S4; 03_Ansvar: 183205; 07_Fase: F90; 02_Prosjekt: 10001574; 06_Omrade: ZV001; 01_Lufthavnkode: ENZV; 05_ID-nummer: +ZV001=245.0001-AV0002T; 04_Kontrakt: 187993
Identity Data - Workset: Workset1
Phasing - Phase Created: Fase 1 - Som bygget
ePset_LocationTool - Splitting: RESULT
ePset_SimplebimBasicQuantities - Area, side, gross, smaller (Simplebim): 0.274115 m2; Area, side, net, smaller (Simplebim): 0.274115 m2; Volume, net (Simplebim): 0.0328938 m3; Area, side, gross, average (Simplebim): 0.274115 m2; Area, side, net, average (Simplebim): 0.274115 m2; Area, side, gross, AABB (Simplebim): 0.46592 m2; Thickness (Simplebim): 120 mm; Length (Simplebim): 512 mm; Height (Simplebim): 910 mm; Area, side, gross, larger (Simplebim): 0.274116 m2; Area, largest surface, net (Simplebim): 0.274116 m2; Area, side, net, larger (Simplebim): 0.274116 m2
ePset_Simplebim - Assembly Level: Leaf
Pset_WallCommon - Reference: ENZV_S-UK01_S70_120mm_OSBG; IsExternal: no; ExtendToStructure: no; LoadBearing: no
Constraints - Top Constraint: Up to level: H03; Base is Attached: no; Related to Mass: no; Room Bounding: yes; Top is Attached: no; Base Constraint: H02; Location Line: Finish Face: Interior

# IfcWall: Basic Wall:Standard - 150mm (3)
In: H01
Type - PredefinedType: STANDARD; Material: Vegg 150 mm
Type - Other - Category: Walls; Family Name: Basic Wall
Type - Construction - Function: Exterior; Width: 150 mm; Wrapping at Inserts: Do not wrap
Type - Graphics - Coarse Scale Fill Color: 12632256; Coarse Scale Fill Pattern: <Solid fill>
Type - Identity Data - Type Name: Standard - 150mm; Workset: Wall Types
Type - Analytical Properties - Absorptance: 0.1; Roughness: 1
ePset_LocationTool - Splitting: RESULT
Cross-Section Definition - Cross-Section: Vertical
Structural - Structural Usage: Non-bearing; Structural: no
Pset_QuantityTakeOff - Reference: Standard - 150mm; sets with these values: 2
ePset_SimplebimBasicQuantities - Thickness (Simplebim): 150 mm
Other - Family: Basic Wall; Family and Type: Basic Wall: Standard - 150mm; Type Id: 129062; Type: Standard - 150mm
Identity Data - Workset: Workset1
Phasing - Phase Created: Fase 1 - Som bygget
Constraints - Base is Attached: no; Related to Mass: no; Room Bounding: yes; Top is Attached: yes; Base Constraint: H01; Location Line: Finish Face: Interior; Top Constraint: Up to level: H02
ePset_Simplebim - Assembly Level: Leaf
Pset_WallCommon - IsExternal: yes; ExtendToStructure: yes; LoadBearing: no; Reference: Standard - 150mm
Name (Basic Wall:Standard - 150mm:...) | Volume, net (Simplebim) (m3) | Area, side, net, average (Simplebim) (m2) = Area, side, gross, average (Simplebim) (m2) | Area, side, gross, larger (Simplebim) (m2) = Area, side, net, larger (Simplebim) (m2) = Area, largest surface, net (Simplebim) (m2) | Area, side, gross, AABB (Simplebim) (m2) | Height (Simplebim) (mm) | Length (Simplebim) (mm) | Area, side, net, smaller (Simplebim) (m2) = Area, side, gross, smaller (Simplebim) (m2)
590791 | 0.287635 | 1.91757 | 1.9178 | 1.91796 | 660 | 2906 | 1.91734
590781 | 0.197871 | 1.31914 | 1.3193 | 1.3194 | 450 | 2932 | 1.31898
590795 | 0.199816 | 1.33211 | 1.33227 | 1.33245 | 450 | 2961 | 1.33195

# IfcWall: Basic Wall:Standard - 246mm, Basic Wall:Standard - 246mm:750435
In: H02
Type - PredefinedType: STANDARD; Material: Vegg 246 mm
Type - Other - Category: Walls; Family Name: Basic Wall
Type - Construction - Function: Exterior; Width: 246 mm; Wrapping at Inserts: Do not wrap
Type - Graphics - Coarse Scale Fill Color: 12632256; Coarse Scale Fill Pattern: <Solid fill>
Type - Identity Data - Type Name: Standard - 246mm; Workset: Wall Types
Type - Analytical Properties - Absorptance: 0.1; Roughness: 1
ePset_LocationTool - Splitting: RESULT
Pset_ReinforcementBarPitchOfWall - Reference: Standard - 246mm; sets with these values: 2
Cross-Section Definition - Cross-Section: Vertical
ePset_SimplebimBasicQuantities - Area, largest surface, net (Simplebim): 25.0777 m2; Area, side, net, larger (Simplebim): 25.0777 m2; Area, side, gross, larger (Simplebim): 89.7748 m2; Volume, net (Simplebim): 6.13631 m3; Area, side, net, average (Simplebim): 24.9633 m2; Area, side, gross, average (Simplebim): 89.6604 m2; Thickness (Simplebim): 246 mm; Height (Simplebim): 4350 mm; Length (Simplebim): 15892 mm; Area, side, net, smaller (Simplebim): 24.8489 m2; Area, side, gross, smaller (Simplebim): 89.546 m2; Area, side, gross, AABB (Simplebim): 69.1302 m2
Structural - Structural Usage: Non-bearing; Structural: no
Identity Data - Workset: Workset1
Phasing - Phase Created: Fase 1 - Som bygget
Pset_WallCommon - Reference: Standard - 246mm; IsExternal: yes; ExtendToStructure: no; LoadBearing: no
ePset_Simplebim - Assembly Level: Leaf
Other - Type: Standard - 246mm; Family: Basic Wall; Family and Type: Basic Wall: Standard - 246mm; Type Id: 744052
Constraints - Top Constraint: Up to level: H03; Base is Attached: no; Related to Mass: no; Room Bounding: yes; Top is Attached: no; Base Constraint: H02; Location Line: Finish Face: Interior

# IfcWallStandardCase: Basic Wall:ENZV_IV-UK02B_S95_133mm_OSBG+G m wrap, Basic Wall:ENZV_IV-UK02B_S95_133mm_OSBG+G m wrap:2600358
In: H02
Type - PredefinedType: STANDARD; Material: A246.Gips 12.5mm fiberarmert -QK5.31112 13 mm, A242.Stender Lettmetall 95mm -PJ3.111002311 95 mm, OSB plate 12 mm, A246.Gips 12.5mm fiberarmert -QK5.31112 13 mm
Type - Other - Category: Walls; Family Name: Basic Wall
Type - Construction - Function: Interior; Width: 133 mm; Wrapping at Ends: Interior; Wrapping at Inserts: Do not wrap; CQMaxWallHeight: 6000 mm
Type - Graphics - Coarse Scale Fill Color: 0
Type - Identity Data - Type Name: ENZV_IV-UK02B_S95_133mm_OSBG+G m wrap; Workset: Wall Types; Type Mark: IV-UK02B
Type - Analytical Properties - Absorptance: 0.1; Roughness: 1
Type - Materials and Finishes - Structural Material: A242.Stender Lettmetall 95mm -PJ3.111002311
Type - Text - Veggtype S: ENZV_IV-UK02_S95_145mm_OSBG
Cross-Section Definition - Cross-Section: Vertical
AVINOR - 08_Status: S4; 03_Ansvar: 183205; 07_Fase: F90; 02_Prosjekt: 10001574; 06_Omrade: ZV001; 01_Lufthavnkode: ENZV; 05_ID-nummer: +ZV001=242.0001-AV0115; 04_Kontrakt: 187993
Structural - Structural Usage: Non-bearing; Structural: no
ePset_LocationTool - Splitting: ORIGINAL
Pset_WallCommon - Reference: ENZV_IV-UK02B_S95_133mm_OSBG+G m wrap; IsExternal: no; ExtendToStructure: no; LoadBearing: no
Identity Data - Workset: Workset1
Phasing - Phase Created: Fase 1 - Som bygget
ePset_Simplebim - Assembly Level: Leaf
ePset_SimplebimBasicQuantities - Thickness (Simplebim): 133 mm; Area, side, gross, AABB (Simplebim): 12.5312 m2; Area, side, net, smaller (Simplebim): 12.5312 m2; Area, side, gross, average (Simplebim): 12.5312 m2; Area, side, gross, smaller (Simplebim): 12.5312 m2; Area, side, gross, larger (Simplebim): 12.5312 m2; Area, largest surface, net (Simplebim): 12.5312 m2; Area, side, net, larger (Simplebim): 12.5312 m2; Area, side, net, average (Simplebim): 12.5312 m2; Length (Simplebim): 3519.99 mm; Height (Simplebim): 3560 mm; Volume, net (Simplebim): 1.66664 m3
Constraints - Top Offset: -340 mm; Top Constraint: Up to level: H03; Base Extension Distance: 0 mm; Base is Attached: no; Base Offset: 0 mm; Related to Mass: no; Room Bounding: no; Top Extension Distance: 0 mm; Top is Attached: no; Base Constraint: H02; Location Line: Core Centerline; Unconnected Height: 3560 mm
Pset_QuantityTakeOff - Reference: ENZV_IV-UK02B_S95_133mm_OSBG+G m wrap; sets with these values: 2
Other - Family: Basic Wall; Type: ENZV_IV-UK02B_S95_133mm_OSBG+G m wrap; Family and Type: Basic Wall: ENZV_IV-UK02B_S95_133mm_OSBG+G m wrap; Type Id: 2600795
Dimensions - Area: 12.5312 m2; Length: 3453.49 mm; Volume: 1.66664 m3

# IfcWallStandardCase: Basic Wall:ENZV_IV-UK02B_S95_145mm_OSBG+G (2)
In: H02
Type - PredefinedType: STANDARD; Material: A246.Gips 12.5mm fiberarmert -QK5.31112 13 mm, A242.Stender Lettmetall 95mm -PJ3.111002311 95 mm, OSB plate 12 mm, A246.Gips 12.5mm fiberarmert -QK5.31112 13 mm
Type - Other - Category: Walls; Family Name: Basic Wall
Type - Construction - Function: Interior; Width: 133 mm; Wrapping at Inserts: Do not wrap; CQMaxWallHeight: 6000 mm
Type - Graphics - Coarse Scale Fill Color: 0
Type - Identity Data - Type Name: ENZV_IV-UK02B_S95_145mm_OSBG+G; Workset: Wall Types; Type Mark: IV-UK02B
Type - Analytical Properties - Absorptance: 0.1; Roughness: 1
Type - Materials and Finishes - Structural Material: A242.Stender Lettmetall 95mm -PJ3.111002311
Type - Text - Veggtype S: ENZV_IV-UK02_S95_145mm_OSBG
Cross-Section Definition - Cross-Section: Vertical
AVINOR - 08_Status: S4; 03_Ansvar: 183205; 07_Fase: F90; 02_Prosjekt: 10001574; 06_Omrade: ZV001; 01_Lufthavnkode: ENZV; 05_ID-nummer: +ZV001=242.0001-AV0115; 04_Kontrakt: 187993
ePset_SimplebimBasicQuantities - Thickness (Simplebim): 133 mm; Height (Simplebim): 3560 mm
Structural - Structural Usage: Non-bearing; Structural: no
ePset_LocationTool - Splitting: ORIGINAL
Pset_QuantityTakeOff - Reference: ENZV_IV-UK02B_S95_145mm_OSBG+G; sets with these values: 2
Pset_WallCommon - Reference: ENZV_IV-UK02B_S95_145mm_OSBG+G; IsExternal: no; ExtendToStructure: no; LoadBearing: no
Identity Data - Workset: Workset1
Phasing - Phase Created: Fase 1 - Som bygget
Other - Family: Basic Wall; Type Id: 2601038; Type: ENZV_IV-UK02B_S95_145mm_OSBG+G; Family and Type: Basic Wall: ENZV_IV-UK02B_S95_145mm_OSBG+G
ePset_Simplebim - Assembly Level: Leaf
Constraints - Top Offset: -340 mm; Top Constraint: Up to level: H03; Base Extension Distance: 0 mm; Base is Attached: no; Base Offset: 0 mm; Related to Mass: no; Top Extension Distance: 0 mm; Top is Attached: no; Base Constraint: H02; Location Line: Core Centerline; Unconnected Height: 3560 mm
Name (Basic Wall:ENZV_IV-UK02B_S95_145mm_OSBG+G:...) | Length (Simplebim) (mm) | Area, side, net, smaller (Simplebim) (m2) | Area, side, gross, smaller (Simplebim) (m2) | Area, side, net, average (Simplebim) (m2) | Area, side, gross, average (Simplebim) (m2) | Area, side, gross, AABB (Simplebim) (m2) | Area, largest surface, net (Simplebim) (m2) = Area, side, net, larger (Simplebim) (m2) = Area (m2) | Area, side, gross, larger (Simplebim) (m2) | Volume, net (Simplebim) (m3) = Volume (m3) | Room Bounding | Length (mm)
1501700 | 6223.46 | 21.8864 | 21.8864 | 21.8864 | 21.8864 | 22.1555 | 21.8864 | 21.8864 | 2.9109 | yes | 6002.38
2610438 | 1765.9 | 3.88643 | 8.14863 | 4.02097 | 8.28317 | 6.28661 | 4.15551 | 8.41771 | 0.534789 | no | 1871.1

# IfcWallStandardCase: Basic Wall:ENZV_IV-UK02_S95_145mm_OSBG, Basic Wall:ENZV_IV-UK02_S95_145mm_OSBG:2108061
In: H02
Type - PredefinedType: STANDARD; Material: A246.Gips 12.5mm fiberarmert -QK5.31112 13 mm, OSB plate 12 mm, A242.Stender Lettmetall 95mm -PJ3.111002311 95 mm, OSB plate 12 mm, A246.Gips 12.5mm fiberarmert -QK5.31112 13 mm
Type - Other - Category: Walls; Family Name: Basic Wall
Type - Construction - Function: Interior; Width: 145 mm; Wrapping at Inserts: Do not wrap; CQMaxWallHeight: 6000 mm
Type - Graphics - Coarse Scale Fill Color: 0
Type - Identity Data - Type Name: ENZV_IV-UK02_S95_145mm_OSBG; Workset: Wall Types; Type Mark: IV-UK02
Type - Analytical Properties - Absorptance: 0.1; Roughness: 1
Type - Materials and Finishes - Structural Material: A242.Stender Lettmetall 95mm -PJ3.111002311
Type - Text - Veggtype S: ENZV_IV-UK02_S95_145mm_OSBG
Cross-Section Definition - Cross-Section: Vertical
Constraints - Top Offset: -340 mm; Location Line: Wall Centerline; Top Constraint: Up to level: H03; Base Extension Distance: 0 mm; Base is Attached: no; Base Offset: 0 mm; Related to Mass: no; Room Bounding: yes; Top Extension Distance: 0 mm; Top is Attached: no; Base Constraint: H02; Unconnected Height: 3560 mm
Structural - Structural Usage: Non-bearing; Structural: no
AVINOR - 08_Status: S4; 03_Ansvar: 183205; 07_Fase: F90; 02_Prosjekt: 10001574; 06_Omrade: ZV001; 05_ID-nummer: +ZV001=242.0001-AV0111; 01_Lufthavnkode: ENZV; 04_Kontrakt: 187993
ePset_LocationTool - Splitting: ORIGINAL
Identity Data - Workset: Workset1
Dimensions - Length: 2952.5 mm; Volume: 1.53053 m3; Area: 10.5554 m2
Other - Type Id: 388076; Type: ENZV_IV-UK02_S95_145mm_OSBG; Family: Basic Wall; Family and Type: Basic Wall: ENZV_IV-UK02_S95_145mm_OSBG
Pset_WallCommon - Reference: ENZV_IV-UK02_S95_145mm_OSBG; IsExternal: no; ExtendToStructure: no; LoadBearing: no
Phasing - Phase Created: Fase 1 - Som bygget
Pset_QuantityTakeOff - Reference: ENZV_IV-UK02_S95_145mm_OSBG; sets with these values: 2
ePset_SimplebimBasicQuantities - Length (Simplebim): 2965 mm; Volume, net (Simplebim): 1.53053 m3; Thickness (Simplebim): 145 mm; Height (Simplebim): 3560 mm; Area, side, gross, AABB (Simplebim): 10.5554 m2; Area, side, net, smaller (Simplebim): 10.5554 m2; Area, side, gross, average (Simplebim): 10.5554 m2; Area, side, gross, smaller (Simplebim): 10.5554 m2; Area, side, gross, larger (Simplebim): 10.5554 m2; Area, largest surface, net (Simplebim): 10.5554 m2; Area, side, net, larger (Simplebim): 10.5554 m2; Area, side, net, average (Simplebim): 10.5554 m2
ePset_Simplebim - Assembly Level: Leaf

# IfcWallStandardCase: Basic Wall:ENZV_O-Flis type 1 - 50x50mm, Basic Wall:ENZV_O-Flis type 1 - 50x50mm:2086620
In: H02
Type - PredefinedType: STANDARD; Material: Fliser 50x50mm hvit 10 mm
Type - Other - Category: Walls; Family Name: Basic Wall
Type - Construction - Function: Exterior; Width: 10 mm; Wrapping at Inserts: Do not wrap
Type - Graphics - Coarse Scale Fill Color: 16777215; Coarse Scale Fill Pattern: <Solid fill>
Type - Identity Data - Type Name: ENZV_O-Flis type 1 - 50x50mm; Workset: Wall Types; Type Mark: O-F01
Type - Analytical Properties - Absorptance: 0.1; Roughness: 1
Type - Materials and Finishes - Structural Material: Fliser 50x50mm hvit
Type - Text - Veggtype S: Flis 10mm
AVINOR - 08_Status: S4; 03_Ansvar: 183205; 07_Fase: F90; 02_Prosjekt: 10001574; 06_Omrade: ZV001; 01_Lufthavnkode: ENZV; 05_ID-nummer: +ZV001=246.0001-EB0026T; 04_Kontrakt: 187993
Cross-Section Definition - Cross-Section: Vertical
Structural - Structural Usage: Non-bearing; Structural: no
Constraints - Top Offset: 0 mm; Base Extension Distance: 0 mm; Base is Attached: no; Base Offset: 0 mm; Related to Mass: no; Room Bounding: yes; Top Extension Distance: 0 mm; Top is Attached: no; Base Constraint: H02; Unconnected Height: 2650 mm; Location Line: Core Face: Interior
Pset_QuantityTakeOff - Reference: ENZV_O-Flis type 1 - 50x50mm; sets with these values: 2
ePset_SimplebimBasicQuantities - Area, side, gross, AABB (Simplebim): 6.7578 m2; Volume, net (Simplebim): 0.067578 m3; Length (Simplebim): 2550.11 mm; Area, side, gross, average (Simplebim): 6.7578 m2; Area, side, net, average (Simplebim): 6.7578 m2; Area, largest surface, net (Simplebim): 6.7578 m2; Area, side, net, larger (Simplebim): 6.7578 m2; Area, side, gross, larger (Simplebim): 6.7578 m2; Area, side, gross, smaller (Simplebim): 6.7578 m2; Area, side, net, smaller (Simplebim): 6.7578 m2; Thickness (Simplebim): 10 mm; Height (Simplebim): 2650 mm
Pset_WallCommon - IsExternal: yes; ExtendToStructure: no; LoadBearing: no; Reference: ENZV_O-Flis type 1 - 50x50mm
Identity Data - Workset: Workset1
Phasing - Phase Created: Fase 1 - Som bygget
Other - Family: Basic Wall; Type Id: 388301; Family and Type: Basic Wall: ENZV_O-Flis type 1 - 50x50mm; Type: ENZV_O-Flis type 1 - 50x50mm
ePset_Simplebim - Assembly Level: Leaf
Dimensions - Area: 6.7578 m2; Length: 2540.11 mm; Volume: 0.067578 m3
ePset_LocationTool - Splitting: ORIGINAL

# IfcWallStandardCase: Basic Wall:ENZV_PV-UK02_S95_120mm_OSBG (5)
In: H02
Type - PredefinedType: STANDARD; Material: A246.Gips 12.5mm fiberarmert -QK5.31112 13 mm, OSB plate 12 mm, A242.Stender Lettmetall 95mm -PJ3.111002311 95 mm
Type - Other - Category: Walls; Family Name: Basic Wall
Type - Construction - Function: Interior; Width: 120 mm; Wrapping at Inserts: Do not wrap; CQMaxWallHeight: 6000 mm
Type - Graphics - Coarse Scale Fill Color: 0
Type - Identity Data - Type Name: ENZV_PV-UK02_S95_120mm_OSBG; Workset: Wall Types; Type Mark: PV-UK02
Type - Analytical Properties - Absorptance: 0.1; Roughness: 1
Type - Materials and Finishes - Structural Material: A242.Stender Lettmetall 95mm -PJ3.111002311
Type - Text - Veggtype S: ENZV_PV-UK01_S70_95mm_OSBG
Constraints - Top Constraint: Up to level: H03; Base Extension Distance: 0 mm; Base is Attached: no; Base Offset: 0 mm; Related to Mass: no; Room Bounding: yes; Top Extension Distance: 0 mm; Top is Attached: no; Base Constraint: H02
Cross-Section Definition - Cross-Section: Vertical
Pset_ReinforcementBarPitchOfWall - Reference: ENZV_PV-UK02_S95_120mm_OSBG; sets with these values: 2
Pset_WallCommon - IsExternal: no; ExtendToStructure: no; LoadBearing: no; Reference: ENZV_PV-UK02_S95_120mm_OSBG
Other - Family: Basic Wall; Family and Type: Basic Wall: ENZV_PV-UK02_S95_120mm_OSBG; Type: ENZV_PV-UK02_S95_120mm_OSBG; Type Id: 389562
ePset_SimplebimBasicQuantities - Thickness (Simplebim): 120 mm
Structural - Structural Usage: Non-bearing; Structural: no
Identity Data - Workset: Workset1
Phasing - Phase Created: Fase 1 - Som bygget
AVINOR - 08_Status: S4; 03_Ansvar: 183205; 07_Fase: F90; 02_Prosjekt: 10001574; 06_Omrade: ZV001; 01_Lufthavnkode: ENZV; 05_ID-nummer: +ZV001=242.0001-AV0114; 04_Kontrakt: 187993
ePset_Simplebim - Assembly Level: Leaf
ePset_LocationTool - Splitting: ORIGINAL
Name (Basic Wall:ENZV_PV-UK02_S95_120mm_OSBG:...) | Top Offset (mm) | Location Line | Unconnected Height (mm) = Height (Simplebim) (mm) | Volume, net (Simplebim) (m3) = Volume (m3) | Area, side, gross, smaller (Simplebim) (m2) = Area, side, net, smaller (Simplebim) (m2) | Area, side, net, average (Simplebim) (m2) = Area, side, gross, average (Simplebim) (m2) | Length (Simplebim) (mm) | Area, largest surface, net (Simplebim) (m2) = Area, side, net, larger (Simplebim) (m2) = Area, side, gross, larger (Simplebim) (m2) = Area (m2) | Area, side, gross, AABB (Simplebim) (m2) | Length (mm)
1952612 | -1420 | Finish Face: Interior | 2480 | 3.12484 | 25.9558 | 26.0403 | 10534.2 | 26.1249 | 26.1249 | 10576.6
2024182 | -340 | Finish Face: Exterior | 3560 | 1.95444 | 16.287 | 16.287 | 4575.01 | 16.287 | 16.287 | 4638.01
2117027 | -340 | Finish Face: Interior | 3560 | 0.0896837 | 0.533758 | 0.747365 | 269.936 | 0.960971 | 0.960971 | 209.934
2132584 | -340 | Finish Face: Interior | 3560 | 0.0923581 | 0.55605 | 0.769651 | 276.198 | 0.983251 | 0.983263 | 276.194
2641173 | -340 | Finish Face: Interior | 3560 | 0.119618 | 0.996813 | 0.996813 | 280.004 | 0.996813 | 0.996813 | 340.004

# IfcWallStandardCase: Basic Wall:ENZV_S-UK01B_S70_108mm_GOSBG, Basic Wall:ENZV_S-UK01B_S70_108mm_GOSBG:2632391
In: H02
Type - PredefinedType: STANDARD; Material: A246.Gips 12.5mm fiberarmert -QK5.31112 13 mm, OSB plate 12 mm, A242.Stender Lettmetall 95mm -PJ3.111002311 70 mm, A246.Gips 12.5mm fiberarmert -QK5.31112 13 mm
Type - Other - Category: Walls; Family Name: Basic Wall
Type - Construction - Function: Interior; Width: 108 mm; Wrapping at Inserts: Do not wrap; CQMaxWallHeight: 6000 mm
Type - Graphics - Coarse Scale Fill Color: 0
Type - Identity Data - Type Name: ENZV_S-UK01B_S70_108mm_GOSBG; Workset: Wall Types; Type Mark: S-UK01B
Type - Analytical Properties - Absorptance: 0.1; Roughness: 1
Type - Materials and Finishes - Structural Material: A242.Stender Lettmetall 95mm -PJ3.111002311
Type - Text - Veggtype S: ENZV_S-UK01_S95_145mm_OSBG
Pset_WallCommon - IsExternal: no; ExtendToStructure: no; LoadBearing: no; Reference: ENZV_S-UK01B_S70_108mm_GOSBG
Cross-Section Definition - Cross-Section: Vertical
ePset_SimplebimBasicQuantities - Area, side, gross, average (Simplebim): 10.0628 m2; Area, side, net, average (Simplebim): 10.0628 m2; Length (Simplebim): 11088.7 mm; Thickness (Simplebim): 108 mm; Height (Simplebim): 910 mm; Area, side, net, larger (Simplebim): 10.0907 m2; Area, largest surface, net (Simplebim): 10.0907 m2; Area, side, gross, larger (Simplebim): 10.0907 m2; Area, side, gross, AABB (Simplebim): 10.0907 m2; Volume, net (Simplebim): 1.08678 m3; Area, side, gross, smaller (Simplebim): 10.0349 m2; Area, side, net, smaller (Simplebim): 10.0349 m2
ePset_LocationTool - Splitting: ORIGINAL
Structural - Structural Usage: Non-bearing; Structural: no
Dimensions - Length: 11213.9 mm; Area: 10.0907 m2; Volume: 1.08678 m3
Identity Data - Workset: Workset1
Pset_ReinforcementBarPitchOfWall - Reference: ENZV_S-UK01B_S70_108mm_GOSBG; sets with these values: 2
Phasing - Phase Created: Fase 1 - Som bygget
ePset_Simplebim - Assembly Level: Leaf
Other - Family: Basic Wall; Family and Type: Basic Wall: ENZV_S-UK01B_S70_108mm_GOSBG; Type: ENZV_S-UK01B_S70_108mm_GOSBG; Type Id: 388763
Constraints - Top Offset: -340 mm; Top Constraint: Up to level: H03; Base Extension Distance: 0 mm; Base is Attached: no; Related to Mass: no; Room Bounding: yes; Top Extension Distance: 0 mm; Top is Attached: no; Base Constraint: H02; Location Line: Core Centerline; Unconnected Height: 910 mm; Base Offset: 2650 mm

# IfcWallStandardCase: Basic Wall:ENZV_S-UK01_S70_120mm_OSBG, Basic Wall:ENZV_S-UK01_S70_120mm_OSBG:1579824
In: H02
Type - PredefinedType: STANDARD; Material: A246.Gips 12.5mm fiberarmert -QK5.31112 13 mm, OSB plate 12 mm, A242.Stender Lettmetall 95mm -PJ3.111002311 70 mm, OSB plate 12 mm, A246.Gips 12.5mm fiberarmert -QK5.31112 13 mm
Type - Other - Category: Walls; Family Name: Basic Wall
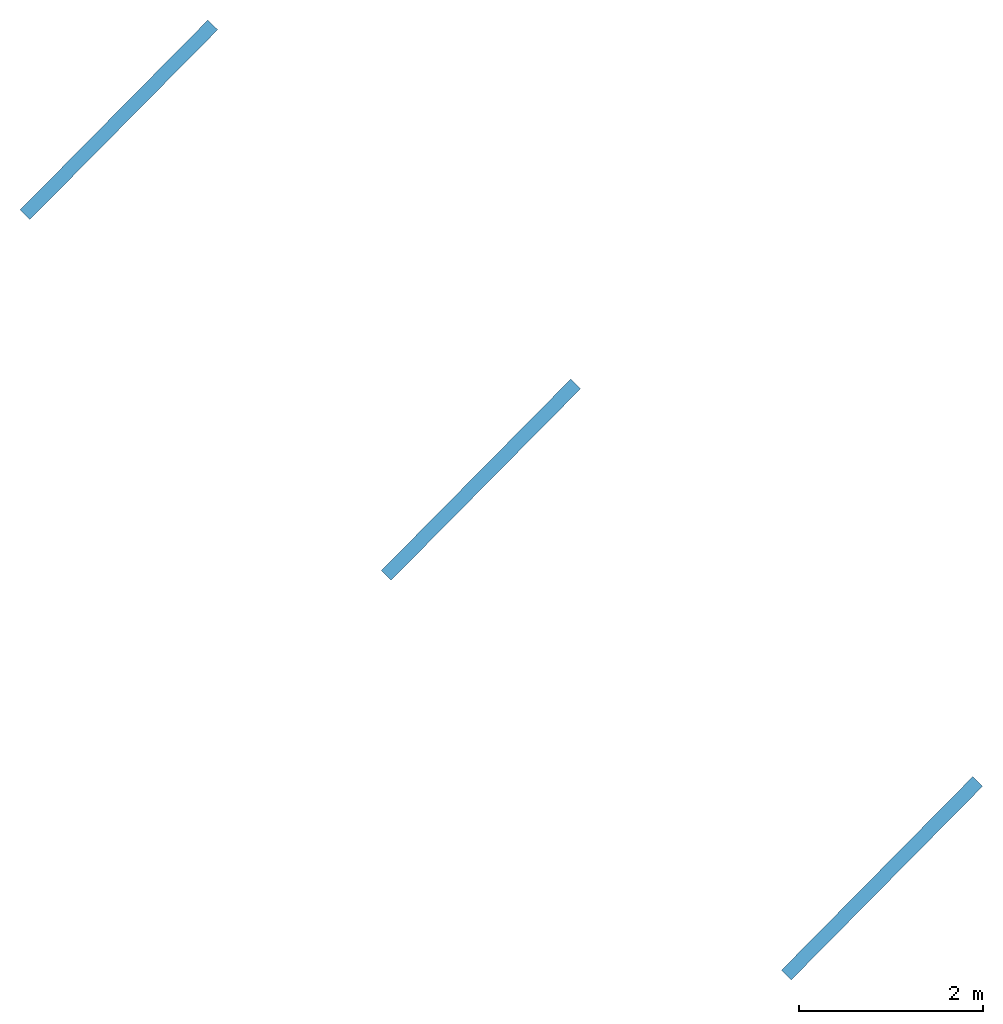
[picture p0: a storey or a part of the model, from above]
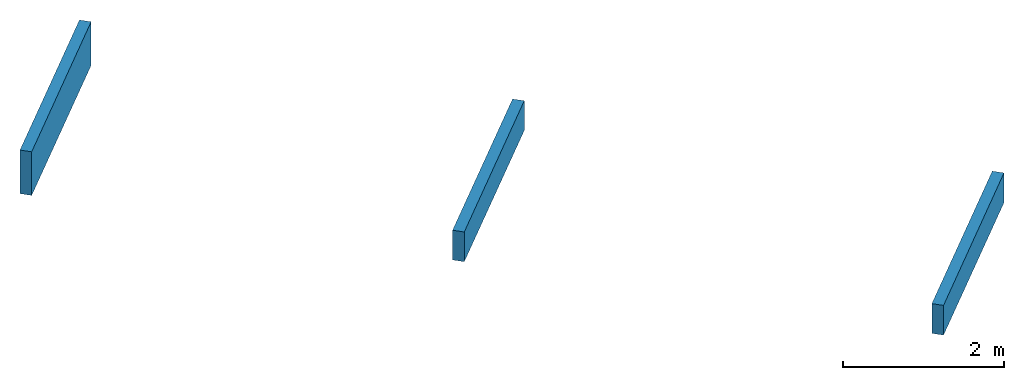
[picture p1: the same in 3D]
Properties of the parts of a building model (IFC2X3), part 2 of 2

# IfcWallStandardCase: Basic Wall:ENZV_S-UK01_S70_120mm_OSBG, Basic Wall:ENZV_S-UK01_S70_120mm_OSBG:1579824
Type - Construction - Function: Interior; Width: 120 mm; Wrapping at Inserts: Do not wrap; CQMaxWallHeight: 6000 mm
Type - Graphics - Coarse Scale Fill Color: 0
Type - Identity Data - Type Name: ENZV_S-UK01_S70_120mm_OSBG; Workset: Wall Types; Type Mark: S-UK01
Type - Analytical Properties - Absorptance: 0.1; Roughness: 1
Type - Materials and Finishes - Structural Material: A242.Stender Lettmetall 95mm -PJ3.111002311
Type - Text - Veggtype S: ENZV_S-UK01_S95_145mm_OSBG
ePset_LocationTool - Splitting: ORIGINAL
Pset_ReinforcementBarPitchOfWall - Reference: ENZV_S-UK01_S70_120mm_OSBG; sets with these values: 2
Other - Type: ENZV_S-UK01_S70_120mm_OSBG; Family: Basic Wall; Family and Type: Basic Wall: ENZV_S-UK01_S70_120mm_OSBG; Type Id: 1646284
Cross-Section Definition - Cross-Section: Vertical
Constraints - Unconnected Height: 910 mm; Top Offset: -2550 mm; Base Extension Distance: 0 mm; Base is Attached: no; Related to Mass: no; Room Bounding: yes; Top Extension Distance: 0 mm; Top is Attached: no; Base Constraint: H02; Location Line: Finish Face: Interior; Base Offset: 2650 mm
Structural - Structural Usage: Non-bearing; Structural: no
AVINOR - 08_Status: S4; 03_Ansvar: 183205; 07_Fase: F90; 02_Prosjekt: 10001574; 06_Omrade: ZV001; 01_Lufthavnkode: ENZV; 05_ID-nummer: +ZV001=245.0001-AV0002T; 04_Kontrakt: 187993
Identity Data - Workset: Workset1
Phasing - Phase Created: Fase 1 - Som bygget
ePset_SimplebimBasicQuantities - Area, side, net, average (Simplebim): 9.54586 m2; Area, side, gross, average (Simplebim): 9.54586 m2; Height (Simplebim): 910 mm; Area, side, net, smaller (Simplebim): 9.53143 m2; Area, side, gross, smaller (Simplebim): 9.53143 m2; Area, side, gross, AABB (Simplebim): 9.53143 m2; Length (Simplebim): 10474.1 mm; Area, largest surface, net (Simplebim): 9.56029 m2; Area, side, net, larger (Simplebim): 9.56029 m2; Area, side, gross, larger (Simplebim): 9.56029 m2; Thickness (Simplebim): 120 mm; Volume, net (Simplebim): 1.13224 m3
ePset_Simplebim - Assembly Level: Leaf
Pset_WallCommon - Reference: ENZV_S-UK01_S70_120mm_OSBG; IsExternal: no; ExtendToStructure: no; LoadBearing: no
Dimensions - Length: 10490 mm; Area: 9.53143 m2; Volume: 1.13224 m3

# IfcWallStandardCase: Basic Wall:ENZV_S-UK03_S95_145mm_OSBG, Basic Wall:ENZV_S-UK03_S95_145mm_OSBG:2608836
In: H02
Type - PredefinedType: STANDARD; Material: A246.Gips 12.5mm fiberarmert -QK5.31112 13 mm, OSB plate 12 mm, A242.Stender Lettmetall 95mm -PJ3.111002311 95 mm, OSB plate 12 mm, A246.Gips 12.5mm fiberarmert -QK5.31112 13 mm
Type - Other - Category: Walls; Family Name: Basic Wall
Type - Construction - Function: Interior; Width: 145 mm; Wrapping at Inserts: Do not wrap; CQMaxWallHeight: 6000 mm
Type - Graphics - Coarse Scale Fill Color: 0
Type - Identity Data - Type Name: ENZV_S-UK03_S95_145mm_OSBG; Workset: Wall Types; Type Mark: S-UK03
Type - Analytical Properties - Absorptance: 0.1; Roughness: 1
Type - Materials and Finishes - Structural Material: A242.Stender Lettmetall 95mm -PJ3.111002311
Type - Text - Veggtype S: ENZV_S-UK01_S95_145mm_OSBG
AVINOR - 08_Status: S4; 03_Ansvar: 183205; 07_Fase: F90; 02_Prosjekt: 10001574; 06_Omrade: ZV001; 01_Lufthavnkode: ENZV; 05_ID-nummer: +ZV001=245.0001-AV0004T; 04_Kontrakt: 187993
Cross-Section Definition - Cross-Section: Vertical
ePset_LocationTool - Splitting: ORIGINAL
Structural - Structural Usage: Non-bearing; Structural: no
Dimensions - Volume: 0.406861 m3; Area: 2.84343 m2; Length: 3219.94 mm
ePset_SimplebimBasicQuantities - Area, side, net, smaller (Simplebim): 2.76844 m2; Area, side, gross, smaller (Simplebim): 2.76844 m2; Length (Simplebim): 3124.65 mm; Area, side, gross, average (Simplebim): 2.80594 m2; Area, side, net, average (Simplebim): 2.80594 m2; Thickness (Simplebim): 145 mm; Volume, net (Simplebim): 0.406861 m3; Height (Simplebim): 910 mm; Area, side, gross, larger (Simplebim): 2.84343 m2; Area, largest surface, net (Simplebim): 2.84343 m2; Area, side, net, larger (Simplebim): 2.84343 m2; Area, side, gross, AABB (Simplebim): 2.84343 m2
Identity Data - Workset: Workset1
Other - Family: Basic Wall; Type: ENZV_S-UK03_S95_145mm_OSBG; Family and Type: Basic Wall: ENZV_S-UK03_S95_145mm_OSBG; Type Id: 2258776
Phasing - Phase Created: Fase 1 - Som bygget
ePset_Simplebim - Assembly Level: Leaf
Pset_WallCommon - Reference: ENZV_S-UK03_S95_145mm_OSBG; IsExternal: no; ExtendToStructure: no; LoadBearing: no
Constraints - Top Offset: -340 mm; Top Constraint: Up to level: H03; Base Extension Distance: 0 mm; Base is Attached: no; Related to Mass: no; Room Bounding: yes; Top Extension Distance: 0 mm; Top is Attached: no; Base Constraint: H02; Location Line: Core Centerline; Unconnected Height: 910 mm; Base Offset: 2650 mm
Pset_ReinforcementBarPitchOfWall - Reference: ENZV_S-UK03_S95_145mm_OSBG; sets with these values: 2

# IfcWallStandardCase: Basic Wall:Standard - 75mm Kjøleromsvegg (8)
In: H02
Type - PredefinedType: STANDARD; Material: Vegg 75 mm
Type - Other - Category: Walls; Family Name: Basic Wall
Type - Construction - Function: Exterior; Width: 75 mm; Wrapping at Inserts: Do not wrap
Type - Graphics - Coarse Scale Fill Color: 16777215; Coarse Scale Fill Pattern: <Solid fill>
Type - Identity Data - Type Name: Standard - 75mm Kjøleromsvegg; Workset: Wall Types; Type Mark: Kjøleromsvegg_75mm
Type - Analytical Properties - Absorptance: 0.1; Roughness: 1
Pset_QuantityTakeOff - Reference: Standard - 75mm Kjøleromsvegg; sets with these values: 2
Cross-Section Definition - Cross-Section: Vertical
Pset_WallCommon - IsExternal: yes; ExtendToStructure: no; LoadBearing: no; Reference: Standard - 75mm Kjøleromsvegg
Structural - Structural Usage: Non-bearing; Structural: no
Identity Data - Workset: Workset1
Phasing - Phase Created: Fase 1 - Som bygget
Other - Type Id: 2607410; Family and Type: Basic Wall: Standard - 75mm Kjøleromsvegg; Family: Basic Wall; Type: Standard - 75mm Kjøleromsvegg
ePset_LocationTool - Splitting: ORIGINAL
ePset_Simplebim - Assembly Level: Leaf
Constraints - Top Offset: -900 mm; Top Constraint: Up to level: H03; Base Extension Distance: 0 mm; Base is Attached: no; Base Offset: 0 mm; Related to Mass: no; Room Bounding: no; Top Extension Distance: 0 mm; Top is Attached: no; Base Constraint: H02; Unconnected Height: 3000 mm; Location Line: Core Face: Exterior
ePset_SimplebimBasicQuantities - Thickness (Simplebim): 75 mm; Height (Simplebim): 3000 mm
AVINOR - 06_Omrade: ZV001; 01_Lufthavnkode: ENZV
Name (Basic Wall:Standard - 75mm Kjøleromsvegg:...) | Area, side, gross, AABB (Simplebim) (m2) = Area, side, gross, average (Simplebim) (m2) = Area, side, gross, smaller (Simplebim) (m2) = Area, side, gross, larger (Simplebim) (m2) | Volume, net (Simplebim) (m3) | Length (Simplebim) (mm) | Area, side, net, smaller (Simplebim) (m2) = Area, side, net, larger (Simplebim) (m2) = Area, largest surface, net (Simplebim) (m2) = Area, side, net, average (Simplebim) (m2) | Length (mm) | Area (m2) | Volume (m3)
2607577 | 13.8327 | 1.03745 | 4610.9 | 13.8327 | 4535.9 | 13.8327 | 1.03745
2607600 | 9.435 | 0.547792 | 3145 | 7.3039 | 3145 | 7.3039 | 0.547792
2607651 | 8.23391 | 0.617543 | 2744.64 | 8.23391 | 2744.64 | 8.23391 | 0.617543
2607663 | 1.63676 | 0.122757 | 545.587 | 1.63676 | 545.587 | 1.63676 | 0.122757
2607694 | 6.66276 | 0.499707 | 2220.92 | 6.66276 | 2220.92 | 6.66276 | 0.499707
2607730 | 4.69596 | 0.352197 | 1565.32 | 4.69596 | 1565.32 | 4.69596 | 0.352197
2607760 | 1.28898 | 0.0966732 | 429.659 | 1.28898 | 429.656 | 1.28897 | 0.0966727
2607786 | 2.87681 | 0.215761 | 958.938 | 2.87681 | 1033.94 | 2.87681 | 0.215761
